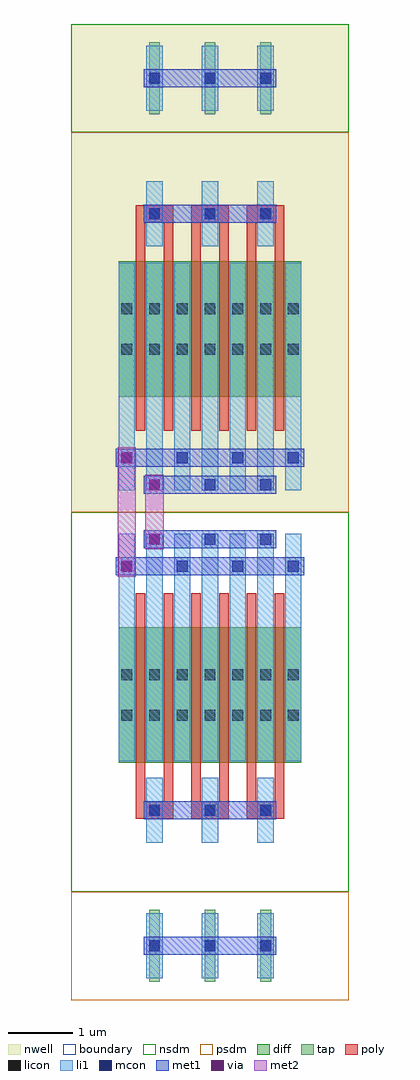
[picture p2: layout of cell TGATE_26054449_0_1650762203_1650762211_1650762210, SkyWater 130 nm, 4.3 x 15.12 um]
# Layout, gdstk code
import gdstk
lib = gdstk.Library(unit=1e-6, precision=1e-09)
def R(c, l, rs):  # rectangles x0, y0, x1, y1
    for r in rs: c.add(gdstk.rectangle(r[:2], r[2:], *l))
def A(c, l, x, y, w, h, nx, ny, dx, dy):  # array of equal rectangles
    R(c, l, [(x+i*dx, y+j*dy, x+i*dx+w, y+j*dy+h) for i in range(nx) for j in range(ny)])
def P(c, l, *ps):  # polygons
    for p in ps: c.add(gdstk.Polygon(p, *l))
nwell = (64, 20)
diff = (65, 20)
tap = (65, 44)
poly = (66, 20)
licon = (66, 44)
li1 = (67, 20)
mcon = (67, 44)
met1 = (68, 20)
via = (68, 44)
met2 = (69, 20)
nsdm = (93, 44)
psdm = (94, 20)
boundary = (235, 4)

nmos_4t_23806256_x3_y1_1 = lib.new_cell('NMOS_4T_23806256_X3_Y1_1650762202_1650762203_1650762211_1650762210')
R(nmos_4t_23806256_x3_y1_1, diff, [(0.735,1.785,3.565,3.885)])
A(nmos_4t_23806256_x3_y1_1, tap, 1.205, 6.16, 0.17, 1.12, 3, 1, 0.86, 0)
A(nmos_4t_23806256_x3_y1_1, poly, 1, 1.26, 0.15, 3.36, 6, 1, 0.43, 0)
A(nmos_4t_23806256_x3_y1_1, poly, 1, 4.485, 0.58, 0.27, 3, 1, 0.86, 0)
A(nmos_4t_23806256_x3_y1_1, licon, 0.775, 2.435, 0.17, 0.17, 3, 2, 0.43, 0.63)
A(nmos_4t_23806256_x3_y1_1, licon, 1.635, 2.435, 0.17, 0.17, 3, 2, 0.43, 0.63)
A(nmos_4t_23806256_x3_y1_1, licon, 2.495, 2.435, 0.17, 0.17, 3, 2, 0.43, 0.63)
A(nmos_4t_23806256_x3_y1_1, licon, 1.205, 4.535, 0.17, 0.17, 3, 2, 0.86, 2.1)
A(nmos_4t_23806256_x3_y1_1, li1, 0.735, 0.335, 0.25, 3.53, 7, 1, 0.43, 0)
A(nmos_4t_23806256_x3_y1_1, li1, 1.165, 4.115, 0.25, 1.01, 3, 2, 0.86, 2.1)
A(nmos_4t_23806256_x3_y1_1, mcon, 1.205, 0.335, 0.17, 0.17, 3, 2, 0.86, 4.2)
A(nmos_4t_23806256_x3_y1_1, mcon, 0.775, 0.755, 0.17, 0.17, 4, 1, 0.86, 0)
A(nmos_4t_23806256_x3_y1_1, mcon, 1.205, 6.635, 0.17, 0.17, 3, 1, 0.86, 0)
R(nmos_4t_23806256_x3_y1_1, met1, [(1.12,0.28,3.18,0.56), (0.69,0.7,3.61,0.98), (1.12,4.48,3.18,4.76), (1.12,6.58,3.18,6.86)])
R(nmos_4t_23806256_x3_y1_1, nsdm, [(0,0,4.3,5.88)])
R(nmos_4t_23806256_x3_y1_1, psdm, [(0,5.88,4.3,7.56)])

pmos_4t_84335382_x3_y1_1 = lib.new_cell('PMOS_4T_84335382_X3_Y1_1650762203_1650762203_1650762211_1650762210')
R(pmos_4t_84335382_x3_y1_1, nwell, [(0,0,4.3,7.56)])
R(pmos_4t_84335382_x3_y1_1, diff, [(0.735,1.785,3.565,3.885)])
A(pmos_4t_84335382_x3_y1_1, tap, 1.205, 6.16, 0.17, 1.12, 3, 1, 0.86, 0)
A(pmos_4t_84335382_x3_y1_1, poly, 1, 1.26, 0.15, 3.36, 6, 1, 0.43, 0)
A(pmos_4t_84335382_x3_y1_1, poly, 1, 4.485, 0.58, 0.27, 3, 1, 0.86, 0)
A(pmos_4t_84335382_x3_y1_1, licon, 0.775, 2.435, 0.17, 0.17, 3, 2, 0.43, 0.63)
A(pmos_4t_84335382_x3_y1_1, licon, 1.635, 2.435, 0.17, 0.17, 3, 2, 0.43, 0.63)
A(pmos_4t_84335382_x3_y1_1, licon, 2.495, 2.435, 0.17, 0.17, 3, 2, 0.43, 0.63)
A(pmos_4t_84335382_x3_y1_1, licon, 1.205, 4.535, 0.17, 0.17, 3, 2, 0.86, 2.1)
A(pmos_4t_84335382_x3_y1_1, li1, 0.735, 0.335, 0.25, 3.53, 7, 1, 0.43, 0)
A(pmos_4t_84335382_x3_y1_1, li1, 1.165, 4.115, 0.25, 1.01, 3, 2, 0.86, 2.1)
A(pmos_4t_84335382_x3_y1_1, mcon, 1.205, 0.335, 0.17, 0.17, 3, 2, 0.86, 4.2)
A(pmos_4t_84335382_x3_y1_1, mcon, 0.775, 0.755, 0.17, 0.17, 4, 1, 0.86, 0)
A(pmos_4t_84335382_x3_y1_1, mcon, 1.205, 6.635, 0.17, 0.17, 3, 1, 0.86, 0)
R(pmos_4t_84335382_x3_y1_1, met1, [(1.12,0.28,3.18,0.56), (0.69,0.7,3.61,0.98), (1.12,4.48,3.18,4.76), (1.12,6.58,3.18,6.86)])
R(pmos_4t_84335382_x3_y1_1, nsdm, [(0,5.88,4.3,7.56)])
R(pmos_4t_84335382_x3_y1_1, psdm, [(0,0,4.3,5.88)])

tgate_26054449_0_1650762 = lib.new_cell('TGATE_26054449_0_1650762203_1650762211_1650762210')
R(tgate_26054449_0_1650762, met1, [(0.7,6.58,1.02,6.86), (0.7,6.58,1.02,6.86), (1.13,7,1.45,7.28), (1.13,7,1.45,7.28), (1.13,7.84,1.45,8.12), (1.13,7.84,1.45,8.12), (0.7,8.26,1.02,8.54), (0.7,8.26,1.02,8.54)])
P(tgate_26054449_0_1650762, met1, [(0,0),(0,0),(0,0),(0,0)],
  [(0,0),(0,0),(0,0),(0,0)],
  [(0,0),(0,0),(0,0),(0,0)],
  [(0,0),(0,0),(0,0),(0,0)],
  [(0,0),(0,0),(0,0),(0,0)],
  [(0,0),(0,0),(0,0),(0,0)],
  [(0,0),(0,0),(0,0),(0,0)],
  [(0,0),(0,0),(0,0),(0,0)])
R(tgate_26054449_0_1650762, via, [(0.785,6.645,0.935,6.795), (0.785,6.645,0.935,6.795), (1.215,7.065,1.365,7.215), (1.215,7.065,1.365,7.215), (1.215,7.905,1.365,8.055), (1.215,7.905,1.365,8.055), (0.785,8.325,0.935,8.475), (0.785,8.325,0.935,8.475)])
R(tgate_26054449_0_1650762, met2, [(0.72,6.56,1,6.88), (0.72,6.56,1,6.88), (0.72,6.72,1,8.4), (1.15,6.98,1.43,7.3), (1.15,6.98,1.43,7.3), (1.15,7.14,1.43,7.98), (1.15,7.82,1.43,8.14), (1.15,7.82,1.43,8.14), (0.72,8.24,1,8.56), (0.72,8.24,1,8.56)])
R(tgate_26054449_0_1650762, boundary, [(0,0,4.3,15.12)])
tgate_26054449_0_1650762.add(gdstk.Reference(nmos_4t_23806256_x3_y1_1, (0,7.56), x_reflection=True))
tgate_26054449_0_1650762.add(gdstk.Reference(pmos_4t_84335382_x3_y1_1, (0,7.56)))

lib.write_gds('TGATE_26054449_0_1650762203_1650762211_1650762210.gds')
